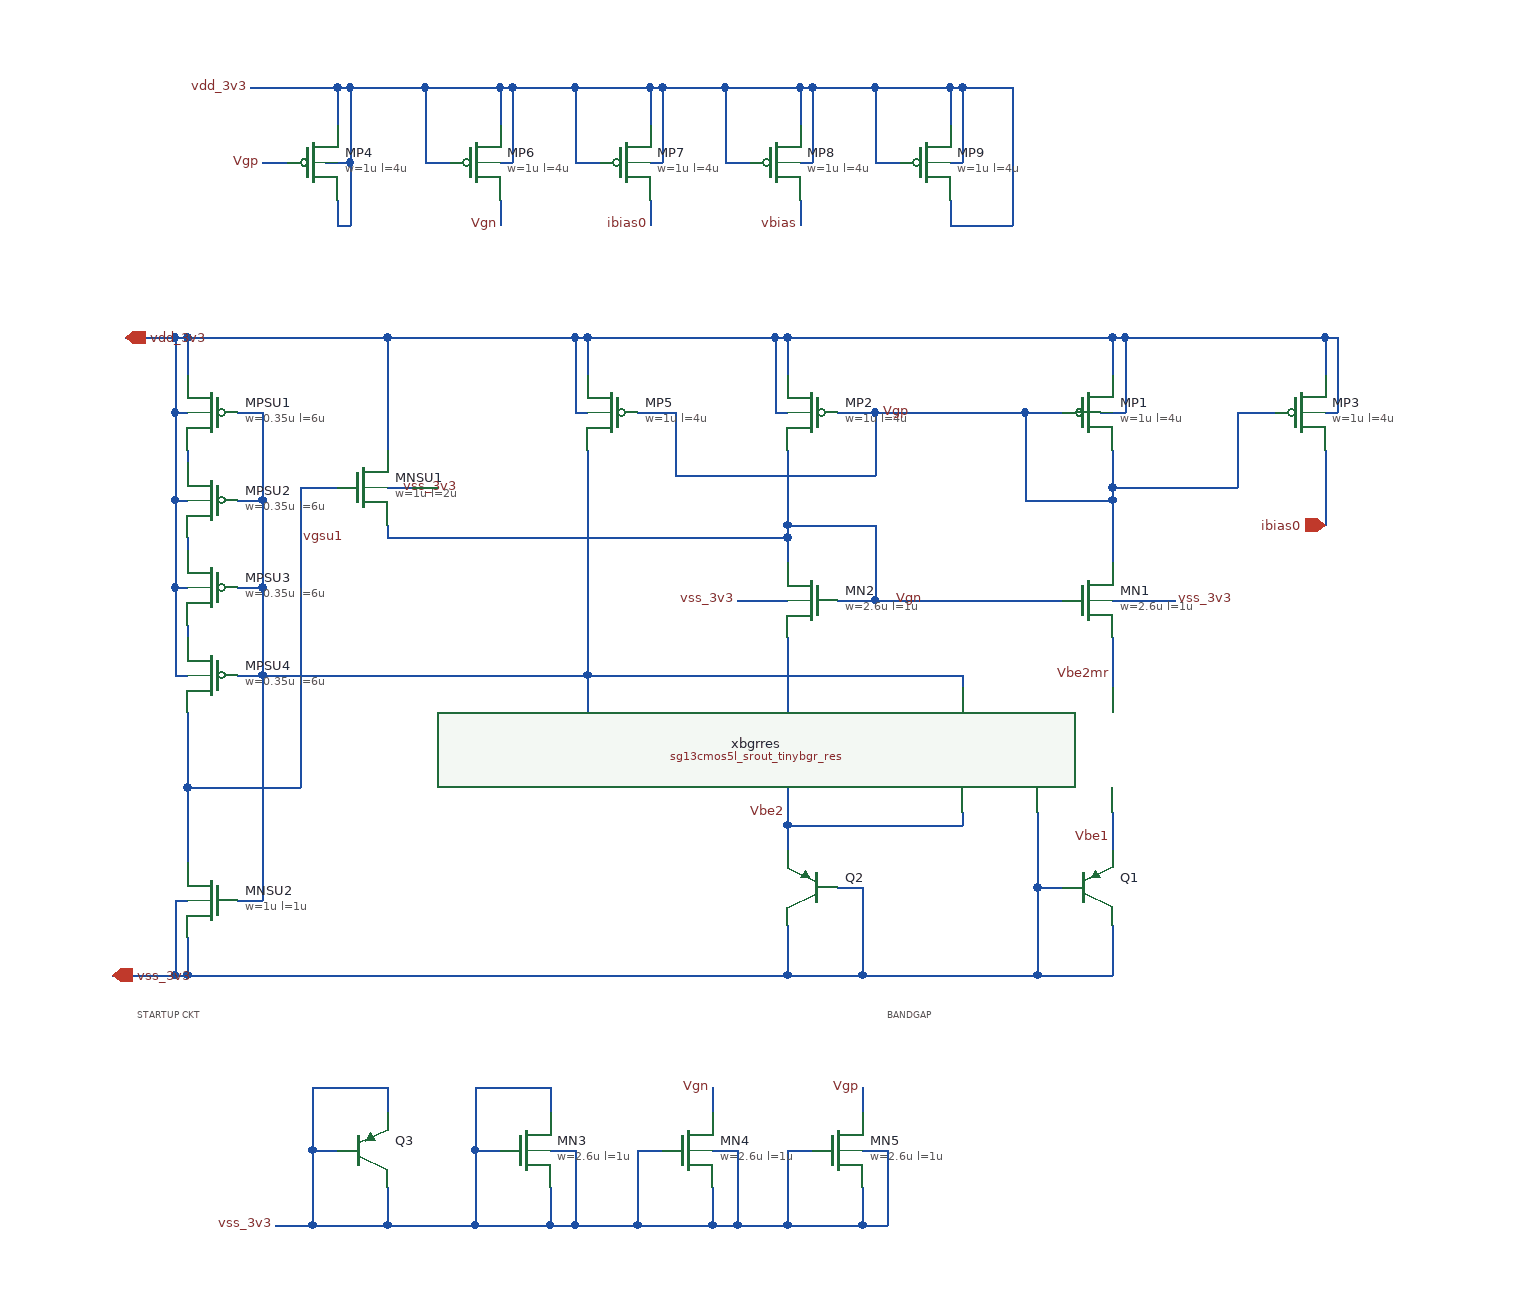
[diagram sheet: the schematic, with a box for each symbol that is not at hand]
v {xschem version=3.4.8RC file_version=1.3}
G {}
K {}
V {}
S {}
F {}
E {}
P 4 1 -10 -540 {}
T {STARTUP CKT} -440 -10 0 0 0.2 0.2 {}
T {BANDGAP} 160 -10 0 0 0.2 0.2 {}
N 120 -100 140 -100 {lab=vss_3v3}
N 140 -100 140 -30 {lab=vss_3v3}
N 80 -30 140 -30 {lab=vss_3v3}
N 80 -70 80 -30 {lab=vss_3v3}
N 280 -30 340 -30 {lab=vss_3v3}
N 340 -70 340 -30 {lab=vss_3v3}
N 280 -100 300 -100 {lab=vss_3v3}
N 280 -100 280 -30 {lab=vss_3v3}
N 80 -380 80 -360 {lab=Vgn}
N 340 -410 340 -360 {lab=Vgp}
N 80 -540 80 -510 {lab=vdd_3v3}
N 340 -540 340 -510 {lab=vdd_3v3}
N 70 -480 80 -480 {lab=vdd_3v3}
N 70 -540 70 -480 {lab=vdd_3v3}
N 70 -540 80 -540 {lab=vdd_3v3}
N 330 -480 350 -480 {lab=vdd_3v3}
N 350 -540 350 -480 {lab=vdd_3v3}
N 340 -540 350 -540 {lab=vdd_3v3}
N 340 -330 390 -330 {lab=vss_3v3}
N 140 -30 280 -30 {lab=vss_3v3}
N 80 -540 340 -540 {lab=vdd_3v3}
N 270 -480 300 -480 {lab=Vgp}
N 270 -480 270 -410 {lab=Vgp}
N 270 -410 340 -410 {lab=Vgp}
N 340 -420 340 -410 {lab=Vgp}
N 80 -390 150 -390 {lab=Vgn}
N 80 -450 80 -390 {lab=Vgn}
N 150 -390 150 -330 {lab=Vgn}
N 120 -330 150 -330 {lab=Vgn}
N -80 -540 70 -540 {lab=vdd_3v3}
N 510 -540 510 -510 {lab=vdd_3v3}
N 350 -540 510 -540 {lab=vdd_3v3}
N 510 -480 520 -480 {lab=vdd_3v3}
N 520 -540 520 -480 {lab=vdd_3v3}
N 510 -540 520 -540 {lab=vdd_3v3}
N 340 -450 340 -420 {lab=Vgp}
N 440 -480 440 -420 {lab=Vgp}
N 440 -480 470 -480 {lab=Vgp}
N 510 -450 510 -390 {lab=ibias0}
N -80 -540 -80 -510 {lab=vdd_3v3}
N -90 -540 -80 -540 {lab=vdd_3v3}
N 150 -480 150 -430 {lab=Vgp}
N 120 -480 150 -480 {lab=Vgp}
N -10 -430 150 -430 {lab=Vgp}
N -10 -480 -10 -430 {lab=Vgp}
N -40 -480 -10 -480 {lab=Vgp}
N -90 -480 -80 -480 {lab=vdd_3v3}
N -90 -540 -90 -480 {lab=vdd_3v3}
N 80 -150 80 -130 {lab=Vbe2}
N 150 -330 300 -330 {lab=Vgn}
N 150 -480 270 -480 {lab=Vgp}
N -80 -450 -80 -270 {lab=vbias}
N -240 -540 -90 -540 {lab=vdd_3v3}
N -240 -420 -220 -420 {lab=vss_3v3}
N -240 -390 -240 -380 {lab=Vgn}
N -240 -380 80 -380 {lab=Vgn}
N 80 -390 80 -380 {lab=Vgn}
N -400 -540 -400 -510 {lab=vdd_3v3}
N -410 -540 -400 -540 {lab=vdd_3v3}
N -410 -480 -400 -480 {lab=vdd_3v3}
N -410 -540 -410 -480 {lab=vdd_3v3}
N -450 -540 -410 -540 {lab=vdd_3v3}
N -360 -480 -340 -480 {lab=vbias}
N -340 -270 -80 -270 {lab=vbias}
N -340 -340 -340 -270 {lab=vbias}
N -400 -450 -400 -440 {lab=#net1}
N -360 -410 -340 -410 {lab=vbias}
N -340 -480 -340 -410 {lab=vbias}
N -410 -410 -400 -410 {lab=vdd_3v3}
N -410 -480 -410 -410 {lab=vdd_3v3}
N -310 -420 -280 -420 {lab=vgsu1}
N -410 -340 -410 -270 {lab=vdd_3v3}
N -410 -270 -400 -270 {lab=vdd_3v3}
N -410 -340 -400 -340 {lab=vdd_3v3}
N 40 -330 80 -330 {lab=vss_3v3}
N 280 -160 280 -100 {lab=vss_3v3}
N 340 -160 340 -130 {lab=Vbe1}
N 340 -300 340 -260 {lab=Vbe2mr}
N 220 -160 220 -150 {lab=Vbe2}
N 80 -150 220 -150 {lab=Vbe2}
N 80 -300 80 -150 {lab=Vbe2}
N 220 -270 220 -260 {lab=vbias}
N -80 -270 220 -270 {lab=vbias}
N -400 -380 -400 -370 {lab=#net2}
N -410 -410 -410 -340 {lab=vdd_3v3}
N -360 -270 -340 -270 {lab=vbias}
N -360 -340 -340 -340 {lab=vbias}
N -340 -410 -340 -340 {lab=vbias}
N -80 -270 -80 -230 {lab=vbias}
N -100 -230 -80 -230 {lab=vbias}
N -240 -540 -240 -450 {lab=vdd_3v3}
N -400 -540 -240 -540 {lab=vdd_3v3}
N -400 -30 80 -30 {lab=vss_3v3}
N -400 -180 -400 -120 {lab=vgsu1}
N -400 -310 -400 -300 {lab=#net3}
N -240 140 -240 170 {lab=vss_3v3}
N -300 170 -240 170 {lab=vss_3v3}
N -300 110 -280 110 {lab=vss_3v3}
N -300 110 -300 170 {lab=vss_3v3}
N -240 60 -240 80 {lab=vss_3v3}
N -300 60 -240 60 {lab=vss_3v3}
N -300 60 -300 110 {lab=vss_3v3}
N -110 140 -110 170 {lab=vss_3v3}
N -170 170 -110 170 {lab=vss_3v3}
N -170 110 -150 110 {lab=vss_3v3}
N -170 110 -170 170 {lab=vss_3v3}
N -240 170 -170 170 {lab=vss_3v3}
N -110 60 -110 80 {lab=vss_3v3}
N -170 60 -110 60 {lab=vss_3v3}
N -170 60 -170 110 {lab=vss_3v3}
N -110 110 -90 110 {lab=vss_3v3}
N -90 110 -90 170 {lab=vss_3v3}
N -110 170 -90 170 {lab=vss_3v3}
N 20 140 20 170 {lab=vss_3v3}
N -40 170 20 170 {lab=vss_3v3}
N -40 110 -20 110 {lab=vss_3v3}
N -40 110 -40 170 {lab=vss_3v3}
N -90 170 -40 170 {lab=vss_3v3}
N 20 110 40 110 {lab=vss_3v3}
N 40 110 40 170 {lab=vss_3v3}
N 20 170 40 170 {lab=vss_3v3}
N 20 60 20 80 {lab=Vgn}
N 140 140 140 170 {lab=vss_3v3}
N 80 170 140 170 {lab=vss_3v3}
N 80 110 100 110 {lab=vss_3v3}
N 80 110 80 170 {lab=vss_3v3}
N 40 170 80 170 {lab=vss_3v3}
N 140 110 160 110 {lab=vss_3v3}
N 160 110 160 170 {lab=vss_3v3}
N 140 170 160 170 {lab=vss_3v3}
N 140 60 140 80 {lab=Vgp}
N 340 -420 440 -420 {lab=Vgp}
N -340 -680 -320 -680 {lab=Vgp}
N -280 -740 -280 -710 {lab=vdd_3v3}
N -290 -680 -270 -680 {lab=vdd_3v3}
N -280 -740 -270 -740 {lab=vdd_3v3}
N -280 -650 -280 -630 {lab=vdd_3v3}
N -280 -630 -270 -630 {lab=vdd_3v3}
N -270 -680 -270 -630 {lab=vdd_3v3}
N -270 -740 -270 -680 {lab=vdd_3v3}
N -150 -740 -150 -710 {lab=vdd_3v3}
N -210 -740 -150 -740 {lab=vdd_3v3}
N -150 -680 -140 -680 {lab=vdd_3v3}
N -140 -740 -140 -680 {lab=vdd_3v3}
N -150 -740 -140 -740 {lab=vdd_3v3}
N -210 -680 -190 -680 {lab=vdd_3v3}
N -210 -740 -210 -680 {lab=vdd_3v3}
N -270 -740 -210 -740 {lab=vdd_3v3}
N -150 -650 -150 -630 {lab=Vgn}
N -30 -740 -30 -710 {lab=vdd_3v3}
N -90 -740 -30 -740 {lab=vdd_3v3}
N -30 -680 -20 -680 {lab=vdd_3v3}
N -20 -740 -20 -680 {lab=vdd_3v3}
N -30 -740 -20 -740 {lab=vdd_3v3}
N -90 -680 -70 -680 {lab=vdd_3v3}
N -90 -740 -90 -680 {lab=vdd_3v3}
N -30 -650 -30 -630 {lab=ibias0}
N -140 -740 -90 -740 {lab=vdd_3v3}
N 90 -740 90 -710 {lab=vdd_3v3}
N 30 -740 90 -740 {lab=vdd_3v3}
N 90 -680 100 -680 {lab=vdd_3v3}
N 100 -740 100 -680 {lab=vdd_3v3}
N 90 -740 100 -740 {lab=vdd_3v3}
N 30 -680 50 -680 {lab=vdd_3v3}
N 30 -740 30 -680 {lab=vdd_3v3}
N 90 -650 90 -630 {lab=VREF}
N -20 -740 30 -740 {lab=vdd_3v3}
N 210 -740 210 -710 {lab=vdd_3v3}
N 150 -740 210 -740 {lab=vdd_3v3}
N 210 -680 220 -680 {lab=vdd_3v3}
N 220 -740 220 -680 {lab=vdd_3v3}
N 210 -740 220 -740 {lab=vdd_3v3}
N 150 -680 170 -680 {lab=vdd_3v3}
N 150 -740 150 -680 {lab=vdd_3v3}
N 210 -650 210 -630 {lab=vdd_3v3}
N 100 -740 150 -740 {lab=vdd_3v3}
N 210 -630 260 -630 {lab=vdd_3v3}
N 260 -740 260 -630 {lab=vdd_3v3}
N 220 -740 260 -740 {lab=vdd_3v3}
N -400 -60 -400 -30 {lab=vss_3v3}
N -410 -30 -400 -30 {lab=vss_3v3}
N -410 -90 -400 -90 {lab=vss_3v3}
N -410 -90 -410 -30 {lab=vss_3v3}
N -460 -30 -410 -30 {lab=vss_3v3}
N -360 -90 -340 -90 {lab=vbias}
N -340 -270 -340 -90 {lab=vbias}
N -400 -180 -310 -180 {lab=vgsu1}
N -350 -740 -280 -740 {lab=vdd_3v3}
N -400 -240 -400 -180 {lab=vgsu1}
N -310 -420 -310 -180 {lab=vgsu1}
N -330 170 -300 170 {lab=vss_3v3}
C {sg13cmos5l_pr/pnpMPA.sym} 320 -100 0 0 {name=Q1
m=8
a=1.4p
p=5.4u}
C {sg13cmos5l_pr/pnpMPA.sym} 100 -100 0 1 {name=Q2
m=1
a=1.4p
p=5.4u}
C {sg13cmos5l_pr/sg13_hv_nmos.sym} 100 -330 0 1 {name=MN2
l=1u
w=2.6u
ng=1
m=6
}
C {sg13cmos5l_pr/sg13_hv_nmos.sym} 320 -330 0 0 {name=MN1
l=1u
w=2.6u
ng=1
m=12
}
C {sg13cmos5l_pr/sg13_hv_pmos.sym} 100 -480 0 1 {name=MP2
l=4u
w=1u
ng=1
m=3
}
C {sg13cmos5l_pr/sg13_hv_pmos.sym} 320 -480 0 0 {name=MP1
l=4u
w=1u
ng=1
m=6
}
C {iopin.sym} -450 -540 0 1 {name=p1 lab=vdd_3v3}
C {iopin.sym} -460 -30 0 1 {name=p2 lab=vss_3v3}
C {lab_wire.sym} 190 -330 0 0 {name=p8 sig_type=std_logic lab=Vgn}
C {lab_wire.sym} 180 -480 0 0 {name=p9 sig_type=std_logic lab=Vgp}
C {opin.sym} -100 -230 0 1 {name=p10 lab=vbias}
C {opin.sym} 510 -390 3 1 {name=p11 lab=ibias0}
C {lab_wire.sym} 40 -330 0 0 {name=p3 sig_type=std_logic lab=vss_3v3}
C {lab_wire.sym} 390 -330 0 1 {name=p4 sig_type=std_logic lab=vss_3v3}
C {sg13cmos5l_pr/sg13_hv_pmos.sym} 490 -480 0 0 {name=MP3
l=4u
w=1u
ng=1
m=11
}
C {sg13cmos5l_pr/sg13_hv_pmos.sym} -60 -480 0 1 {name=MP5
l=4u
w=1u
ng=1
m=3
}
C {sg13cmos5l_pr/sg13_hv_nmos.sym} -260 -420 0 0 {name=MNSU1
l=2u
w=1u
ng=1
m=1
}
C {sg13cmos5l_pr/sg13_hv_pmos.sym} -380 -480 0 1 {name=MPSU1
l=6u
w=0.35u
ng=1
m=1
}
C {sg13cmos5l_pr/sg13_hv_nmos.sym} -380 -90 0 1 {name=MNSU2
l=1u
w=1u
ng=1
m=1
}
C {lab_wire.sym} -230 -420 0 1 {name=p13 sig_type=std_logic lab=vss_3v3}
C {lab_wire.sym} -310 -380 0 1 {name=p15 sig_type=std_logic lab=vgsu1}
C {sg13cmos5l_pr/sg13_hv_pmos.sym} -380 -410 0 1 {name=MPSU2
l=6u
w=0.35u
ng=1
m=1
}
C {sg13cmos5l_pr/sg13_hv_pmos.sym} -380 -340 0 1 {name=MPSU3
l=6u
w=0.35u
ng=1
m=1
}
C {sg13cmos5l_pr/sg13_hv_pmos.sym} -380 -270 0 1 {name=MPSU4
l=6u
w=0.35u
ng=1
m=1
}
C {lab_wire.sym} 80 -160 0 0 {name=p5 sig_type=std_logic lab=Vbe2}
C {lab_wire.sym} 340 -140 0 0 {name=p6 sig_type=std_logic lab=Vbe1}
C {lab_wire.sym} 340 -270 0 0 {name=p7 sig_type=std_logic lab=Vbe2mr}
C {sg13cmos5l_srout_tinybgr_res.sym} 280 -160 0 0 {name=xbgrres}
C {sg13cmos5l_pr/pnpMPA.sym} -260 110 0 0 {name=Q3
m=2
a=1.4p
p=5.4u}
C {sg13cmos5l_pr/sg13_hv_nmos.sym} -130 110 0 0 {name=MN3
l=1u
w=2.6u
ng=1
m=2
}
C {sg13cmos5l_pr/sg13_hv_nmos.sym} 0 110 0 0 {name=MN4
l=1u
w=2.6u
ng=1
m=2
}
C {lab_wire.sym} 20 60 0 0 {name=p12 sig_type=std_logic lab=Vgn}
C {sg13cmos5l_pr/sg13_hv_nmos.sym} 120 110 0 0 {name=MN5
l=1u
w=2.6u
ng=1
m=4
}
C {lab_wire.sym} 140 60 0 0 {name=p14 sig_type=std_logic lab=Vgp}
C {sg13cmos5l_pr/sg13_hv_pmos.sym} -300 -680 0 0 {name=MP4
l=4u
w=1u
ng=1
m=4
}
C {sg13cmos5l_pr/sg13_hv_pmos.sym} -170 -680 0 0 {name=MP6
l=4u
w=1u
ng=1
m=1
}
C {lab_wire.sym} -150 -630 0 0 {name=p16 sig_type=std_logic lab=Vgn}
C {sg13cmos5l_pr/sg13_hv_pmos.sym} -50 -680 0 0 {name=MP7
l=4u
w=1u
ng=1
m=1
}
C {lab_wire.sym} -30 -630 0 0 {name=p17 sig_type=std_logic lab=ibias0}
C {sg13cmos5l_pr/sg13_hv_pmos.sym} 70 -680 0 0 {name=MP8
l=4u
w=1u
ng=1
m=1
}
C {lab_wire.sym} 90 -630 0 0 {name=p18 sig_type=std_logic lab=vbias}
C {sg13cmos5l_pr/sg13_hv_pmos.sym} 190 -680 0 0 {name=MP9
l=4u
w=1u
ng=1
m=9
}
C {lab_wire.sym} -340 -680 0 0 {name=p19 sig_type=std_logic lab=Vgp}
C {lab_wire.sym} -350 -740 0 0 {name=p20 sig_type=std_logic lab=vdd_3v3}
C {lab_wire.sym} -330 170 0 0 {name=p21 sig_type=std_logic lab=vss_3v3}
